VERSION 5.8 ;
BUSBITCHARS "[]" ;
DIVIDERCHAR "/" ;
UNITS
    DATABASE MICRONS 1000 ;
END UNITS

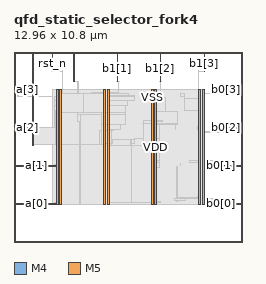
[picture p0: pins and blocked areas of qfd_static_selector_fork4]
MACRO qfd_static_selector_fork4
  FOREIGN qfd_static_selector_fork4 0 0 ;
  CLASS BLOCK ;
  SIZE 12.96 BY 10.8 ;
  PIN a[0]
    DIRECTION INPUT ;
    USE SIGNAL ;
    PORT
      LAYER M4 ;
        RECT  0 2.16 0.192 2.184 ;
    END
    PORT
      LAYER M4 ;
        RECT  0.156 2.16 2.408 2.184 ;
    END
  END a[0]
  PIN a[1]
    DIRECTION INPUT ;
    USE SIGNAL ;
    PORT
      LAYER M4 ;
        RECT  0 4.32 0.192 4.344 ;
    END
    PORT
      LAYER M4 ;
        RECT  0.156 4.32 2.408 4.344 ;
    END
  END a[1]
  PIN a[2]
    DIRECTION INPUT ;
    USE SIGNAL ;
    PORT
      LAYER M4 ;
        RECT  0 6.48 0.192 6.504 ;
    END
    PORT
      LAYER M4 ;
        RECT  0.156 6.48 1.045 6.504 ;
    END
  END a[2]
  PIN a[3]
    DIRECTION INPUT ;
    USE SIGNAL ;
    PORT
      LAYER M4 ;
        RECT  0 8.64 0.192 8.664 ;
    END
    PORT
      LAYER M4 ;
        RECT  0.156 8.64 0.245 8.664 ;
    END
  END a[3]
  PIN b0[0]
    DIRECTION OUTPUT ;
    USE SIGNAL ;
    PORT
      LAYER M4 ;
        RECT  12.768 2.16 12.96 2.184 ;
    END
    PORT
      LAYER M4 ;
        RECT  10.804 2.16 12.78 2.184 ;
    END
  END b0[0]
  PIN b0[1]
    DIRECTION OUTPUT ;
    USE SIGNAL ;
    PORT
      LAYER M4 ;
        RECT  12.768 4.32 12.96 4.344 ;
    END
    PORT
      LAYER M4 ;
        RECT  10.804 4.32 12.78 4.344 ;
    END
  END b0[1]
  PIN b0[2]
    DIRECTION OUTPUT ;
    USE SIGNAL ;
    PORT
      LAYER M4 ;
        RECT  12.768 6.48 12.96 6.504 ;
    END
    PORT
      LAYER M4 ;
        RECT  11.977 6.48 12.78 6.504 ;
    END
  END b0[2]
  PIN b0[3]
    DIRECTION OUTPUT ;
    USE SIGNAL ;
    PORT
      LAYER M4 ;
        RECT  12.768 8.64 12.96 8.664 ;
    END
    PORT
      LAYER M4 ;
        RECT  11.977 8.64 12.78 8.664 ;
    END
  END b0[3]
  PIN b1[0]
    DIRECTION OUTPUT ;
    USE SIGNAL ;
    PORT
      LAYER M5 ;
        RECT  3.408 10.608 3.432 10.8 ;
    END
    PORT
      LAYER M5 ;
        RECT  3.408 9.109 3.432 10.64 ;
    END
  END b1[0]
  PIN b1[1]
    DIRECTION OUTPUT ;
    USE SIGNAL ;
    PORT
      LAYER M5 ;
        RECT  5.856 10.608 5.88 10.8 ;
    END
    PORT
      LAYER M5 ;
        RECT  5.856 9.109 5.88 10.64 ;
    END
  END b1[1]
  PIN b1[2]
    DIRECTION OUTPUT ;
    USE SIGNAL ;
    PORT
      LAYER M5 ;
        RECT  8.304 10.608 8.328 10.8 ;
    END
    PORT
      LAYER M5 ;
        RECT  8.304 9.109 8.328 10.64 ;
    END
  END b1[2]
  PIN b1[3]
    DIRECTION OUTPUT ;
    USE SIGNAL ;
    PORT
      LAYER M5 ;
        RECT  10.8 10.608 10.824 10.8 ;
    END
    PORT
      LAYER M5 ;
        RECT  10.8 9.685 10.824 10.64 ;
    END
  END b1[3]
  PIN ck
    DIRECTION INPUT ;
    USE SIGNAL ;
    PORT
      LAYER M5 ;
        RECT  1.056 10.608 1.08 10.8 ;
    END
    PORT
      LAYER M5 ;
        RECT  1.056 5.509 1.08 10.64 ;
    END
  END ck
  PIN rst_n
    DIRECTION INPUT ;
    USE SIGNAL ;
    PORT
      LAYER M5 ;
        RECT  2.16 10.608 2.184 10.8 ;
    END
    PORT
      LAYER M5 ;
        RECT  2.16 9.685 2.184 10.64 ;
    END
  END rst_n
  PIN VDD
    DIRECTION INOUT ;
    USE POWER ;
    PORT
      LAYER M5 ;
        RECT  10.692 2.151 10.812 8.649 ;
        RECT  7.992 2.151 8.112 8.649 ;
        RECT  5.292 2.151 5.412 8.649 ;
        RECT  2.592 2.151 2.712 8.649 ;
    END
  END VDD
  PIN VSS
    DIRECTION INOUT ;
    USE GROUND ;
    PORT
      LAYER M5 ;
        RECT  10.5 2.137 10.62 8.663 ;
        RECT  7.8 2.137 7.92 8.663 ;
        RECT  5.1 2.137 5.22 8.663 ;
        RECT  2.4 2.137 2.52 8.663 ;
    END
  END VSS
  # OT_OBS_CLOSED layer=M5 d_um=1.536 added=7
  OBS
    LAYER RVTN ;
     RECT  2.16 2.16 10.8 2.295 ;
     RECT  2.16 2.565 10.8 2.835 ;
     RECT  2.16 3.105 10.8 3.375 ;
     RECT  2.16 3.645 10.8 3.915 ;
     RECT  2.16 4.185 10.8 4.455 ;
     RECT  2.16 4.725 10.8 4.995 ;
     RECT  2.16 5.265 10.8 5.535 ;
     RECT  2.16 5.805 10.8 6.075 ;
     RECT  2.16 6.345 10.8 6.615 ;
     RECT  2.16 6.885 10.8 7.155 ;
     RECT  2.16 7.425 10.8 7.695 ;
     RECT  2.16 7.965 10.8 8.235 ;
     RECT  2.16 8.505 10.8 8.64 ;
    LAYER RVTP ;
     RECT  2.16 2.295 10.8 2.565 ;
     RECT  2.16 2.835 10.8 3.105 ;
     RECT  2.16 3.375 10.8 3.645 ;
     RECT  2.16 3.915 10.8 4.185 ;
     RECT  2.16 4.455 10.8 4.725 ;
     RECT  2.16 4.995 10.8 5.265 ;
     RECT  2.16 5.535 10.8 5.805 ;
     RECT  2.16 6.075 10.8 6.345 ;
     RECT  2.16 6.615 10.8 6.885 ;
     RECT  2.16 7.155 10.8 7.425 ;
     RECT  2.16 7.695 10.8 7.965 ;
     RECT  2.16 8.235 10.8 8.505 ;
    LAYER M1 ;
     RECT  2.16 2.151 10.8 8.649 ;
    LAYER M2 ;
     RECT  0.211 8.28 2.16 8.298 ;
     RECT  2.16 2.151 10.8 8.649 ;
     RECT  10.8 2.421 10.812 8.46 ;
     RECT  10.812 2.466 11.435 2.484 ;
     RECT  10.812 4.626 11.435 4.644 ;
     RECT  10.812 6.246 12.011 6.264 ;
     RECT  10.812 8.442 12.011 8.46 ;
    LAYER M3 ;
     RECT  2.415 2.143 2.505 2.155 ;
     RECT  7.815 2.143 7.905 2.251 ;
     RECT  2.304 2.155 2.505 2.255 ;
     RECT  7.815 2.251 8.298 2.291 ;
     RECT  9.252 2.299 9.27 2.335 ;
     RECT  9.144 2.335 9.27 2.371 ;
     RECT  2.415 2.255 2.505 2.413 ;
     RECT  5.115 2.143 5.205 2.413 ;
     RECT  10.515 2.143 10.605 2.413 ;
     RECT  11.412 2.155 11.43 2.413 ;
     RECT  9.144 2.371 9.774 2.461 ;
     RECT  10.515 2.413 11.43 2.461 ;
     RECT  9.144 2.461 11.43 2.489 ;
     RECT  9.252 2.489 10.797 2.525 ;
     RECT  10.44 2.525 10.797 2.561 ;
     RECT  7.815 2.291 8.097 4.261 ;
     RECT  9.252 2.525 9.27 4.289 ;
     RECT  2.415 2.413 2.697 4.315 ;
     RECT  10.515 2.561 10.797 4.315 ;
     RECT  2.304 4.315 2.697 4.415 ;
     RECT  6.66 4.411 6.678 4.451 ;
     RECT  9.468 4.351 9.486 4.451 ;
     RECT  7.632 4.261 8.262 4.495 ;
     RECT  10.515 4.315 11.43 4.531 ;
     RECT  7.524 4.495 8.262 4.649 ;
     RECT  9.972 4.531 11.43 4.649 ;
     RECT  5.115 2.413 5.397 5.503 ;
     RECT  6.66 5.419 6.678 5.575 ;
     RECT  5.115 5.503 5.418 5.605 ;
     RECT  6.66 5.575 6.858 5.843 ;
     RECT  6.84 5.843 6.858 5.881 ;
     RECT  7.815 4.649 8.262 5.881 ;
     RECT  6.84 5.881 8.262 5.909 ;
     RECT  5.115 5.605 5.562 6.277 ;
     RECT  4.896 6.277 5.562 6.317 ;
     RECT  5.04 6.317 5.562 6.349 ;
     RECT  10.515 4.649 10.797 6.385 ;
     RECT  5.04 6.349 5.67 6.421 ;
     RECT  2.415 4.415 2.697 6.475 ;
     RECT  11.988 6.241 12.006 6.509 ;
     RECT  10.44 6.385 10.797 6.539 ;
     RECT  9.18 6.421 9.198 6.655 ;
     RECT  5.04 6.421 6.03 6.691 ;
     RECT  7.344 5.909 8.262 6.691 ;
     RECT  9.18 6.655 9.27 6.691 ;
     RECT  7.344 6.691 9.27 6.749 ;
     RECT  3.744 2.191 3.762 6.853 ;
     RECT  3.636 6.853 3.762 7.231 ;
     RECT  5.04 6.691 6.354 7.231 ;
     RECT  10.515 6.539 10.797 7.321 ;
     RECT  3.636 7.231 6.354 7.339 ;
     RECT  2.304 6.475 2.697 7.357 ;
     RECT  7.815 6.749 9.27 7.421 ;
     RECT  10.476 7.321 10.797 7.465 ;
     RECT  10.296 7.465 10.797 7.501 ;
     RECT  2.304 7.357 2.754 7.735 ;
     RECT  3.492 7.339 6.354 7.735 ;
     RECT  2.304 7.735 6.354 7.771 ;
     RECT  2.304 7.771 6.462 8.041 ;
     RECT  9.684 7.501 10.797 8.159 ;
     RECT  7.815 7.421 8.622 8.231 ;
     RECT  2.304 8.041 6.858 8.267 ;
     RECT  9.684 8.159 9.702 8.275 ;
     RECT  2.412 8.267 6.858 8.339 ;
     RECT  10.476 8.159 10.797 8.387 ;
     RECT  9.468 8.275 9.702 8.429 ;
     RECT  2.412 8.339 6.534 8.465 ;
     RECT  7.815 8.231 8.406 8.465 ;
     RECT  4.392 8.465 5.958 8.501 ;
     RECT  2.415 8.465 2.754 8.657 ;
     RECT  5.115 8.501 5.205 8.657 ;
     RECT  7.815 8.465 8.334 8.657 ;
     RECT  10.476 8.387 10.605 8.657 ;
     RECT  0.216 8.275 0.234 8.669 ;
     RECT  11.988 8.437 12.006 8.669 ;
     RECT  3.636 8.465 3.654 9.149 ;
     RECT  5.94 8.501 5.958 9.149 ;
     RECT  8.316 8.657 8.334 9.149 ;
     RECT  2.736 8.657 2.754 9.725 ;
     RECT  10.476 8.657 10.494 9.725 ;
    LAYER M4 ;
     RECT  1.045 5.52 2.365 6.504 ;
     RECT  2.365 5.52 2.408 7.464 ;
     RECT  2.408 2.148 2.512 8.652 ;
     RECT  2.512 2.418 2.704 8.652 ;
     RECT  2.149 9.696 2.765 9.72 ;
     RECT  2.704 7.344 3.521 7.464 ;
     RECT  3.397 9.12 3.665 9.144 ;
     RECT  3.884 8.4 3.971 8.424 ;
     RECT  2.704 5.52 4.885 5.544 ;
     RECT  4.885 5.52 4.981 6.312 ;
     RECT  3.521 7.344 4.981 7.368 ;
     RECT  4.981 5.52 5.108 7.368 ;
     RECT  5.108 2.148 5.212 8.652 ;
     RECT  5.212 2.418 5.404 8.652 ;
     RECT  5.404 5.52 5.429 6.312 ;
     RECT  5.429 5.616 5.555 6.312 ;
     RECT  5.555 5.616 5.596 5.832 ;
     RECT  5.845 9.12 5.969 9.144 ;
     RECT  5.596 5.808 6.62 5.832 ;
     RECT  6.62 5.424 6.689 5.832 ;
     RECT  6.62 4.416 6.707 4.44 ;
     RECT  6.689 5.424 6.707 5.448 ;
     RECT  7.292 6.72 7.333 6.744 ;
     RECT  6.661 2.256 7.808 2.28 ;
     RECT  7.333 6.72 7.808 6.888 ;
     RECT  7.808 2.148 7.912 8.652 ;
     RECT  7.912 2.256 8.104 8.652 ;
     RECT  8.104 2.256 8.309 2.28 ;
     RECT  8.293 9.12 8.38 9.144 ;
     RECT  8.104 6.864 8.417 6.888 ;
     RECT  10.508 2.148 10.612 8.652 ;
     RECT  10.612 2.16 10.804 8.382 ;
     RECT  10.465 9.696 10.835 9.72 ;
    LAYER M5 ;
     RECT  2.4 2.137 2.52 2.151 ;
     RECT  5.1 2.137 5.22 2.151 ;
     RECT  7.8 2.137 7.92 2.151 ;
     RECT  10.5 2.137 10.62 2.151 ;
     RECT  6.672 2.245 6.696 5.459 ;
     RECT  5.1 2.151 5.412 5.605 ;
     RECT  5.1 5.605 5.544 6.323 ;
     RECT  5.1 6.323 5.412 6.661 ;
     RECT  7.8 2.151 8.112 6.709 ;
     RECT  7.344 6.709 8.112 6.899 ;
     RECT  4.992 6.661 5.412 7.379 ;
     RECT  3.936 7.333 3.96 8.435 ;
     RECT  10.5 2.151 10.812 8.649 ;
     RECT  2.4 2.151 2.712 8.663 ;
     RECT  5.1 7.379 5.412 8.663 ;
     RECT  7.8 6.899 8.112 8.663 ;
     RECT  10.5 8.649 10.62 8.663 ;
     RECT  5.412 2.245 6.672 5.459 ;
     RECT  6.696 2.245 7.8 5.459 ;
     RECT  5.412 5.459 5.544 5.605 ;
     RECT  7.344 5.459 7.8 6.709 ;
     RECT  2.712 7.333 3.936 8.435 ;
     RECT  3.96 7.333 4.992 7.379 ;
     RECT  3.96 7.379 5.1 8.435 ;
  END
END qfd_static_selector_fork4
END LIBRARY
